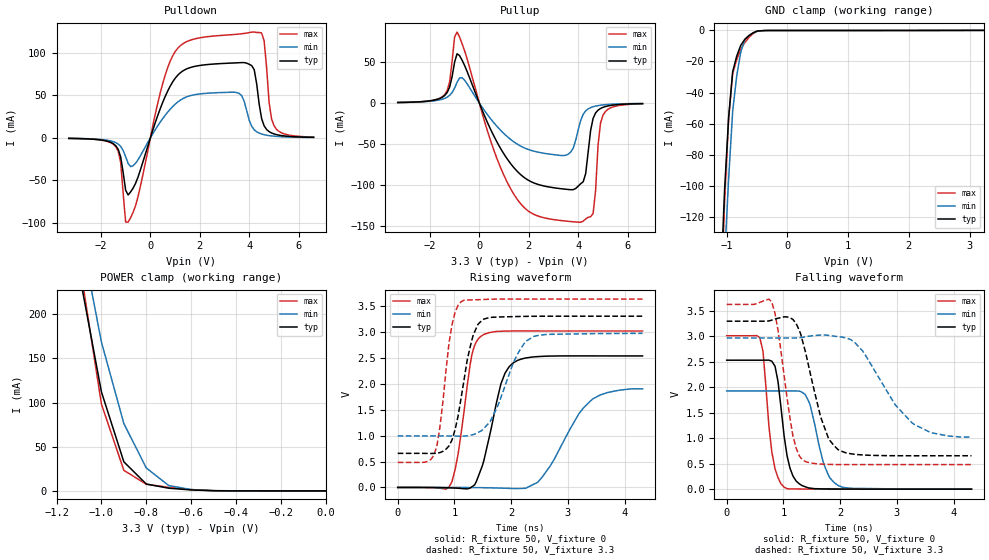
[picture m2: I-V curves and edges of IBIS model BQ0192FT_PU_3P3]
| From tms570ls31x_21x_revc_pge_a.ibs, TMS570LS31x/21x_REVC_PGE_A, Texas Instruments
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|   Model Cell BQ0192FT_PU_3P3
|BQ0192FT_PU_3P3
[Model]   BQ0192FT_PU_3P3
Model_type   I/O
Polarity   Non-Inverting
Enable   Active-Low
Vinl =  1.15
Vinh =  1.55
Cref =  15.0001pF
Rref =  101.0000M
Vref =  0V
Vmeas =  1.65
C_comp   1.2p   1.2p   1.2p
[Model Spec]
Vinl   1.15   1.02   1.28
Vinh   1.55   1.45   1.65
[Temperature Range]   25   155   -40
[Voltage Range]   3.3   2.97   3.63
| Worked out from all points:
|   slope of the pulldown table from 0 to 0.495 V, typ, clamps not added: 11.9 ohm
|   slope of the pullup table from 0 to 0.495 V, typ, clamps not added: 14.3 ohm
|   GND clamp passes 1 mA (typ) near -0.53 V on its own axis
|   POWER clamp passes 1 mA (typ) near -0.59 V on its own axis
|   rising waveform, R_fixture 50, V_fixture 0: 20-80 % time 315ps typ, 599ps min, 226ps max; typ from 0.001 V to 2.53 V
|   rising waveform, R_fixture 50, V_fixture 3.3: 20-80 % time 265ps typ, 431ps min, 200ps max; typ from 0.658 V to 3.3 V
|   falling waveform, R_fixture 50, V_fixture 0: 20-80 % time 182ps typ, 257ps min, 155ps max; typ from 2.53 V to 0.001 V
|   falling waveform, R_fixture 50, V_fixture 3.3: 20-80 % time 362ps typ, 701ps min, 238ps max; typ from 3.3 V to 0.658 V
[POWER_clamp]
|   voltage   I(typ)   I(min)   I(max)
-3.3V     4.054A     4.63A      4.887A
-1.1V     248.3mA    301mA      262.8mA
-1.067V   202.9mA    256.9mA    208mA
-1.033V   157.6mA    212.7mA    153.2mA
-1V       112.2mA    168.6mA    98.37mA
-900mV    32.94mA    76.25mA    23.31mA
-800mV    7.767mA    25.97mA    7.563mA
-700mV    3.087mA    6.069mA    4.066mA
-600mV    1.133mA    1.556mA    1.49mA
-500mV    225uA      392.2uA    256.9uA
0V        441.5pA    6.157nA    415.4pA
[Pulldown]
|   voltage   I(typ)   I(min)   I(max)
-3.3V     -593uA     -522.6uA   -580.3uA
-1.4V     -9.188mA   -5.565mA   -10.35mA
-1.2V     -22.55mA   -10.08mA   -29.13mA
-1V       -61.66mA   -22.23mA   -99.07mA
-900mV    -67.21mA   -30.1mA    -99.29mA
1V        70.16mA    39.61mA    101.5mA
3.5V      88.44mA    53.41mA    122.1mA
4.2V      80.27mA    9.542mA    124.6mA
4.6V      14.18mA    3.749mA    114.2mA
4.8V      7.418mA    2.695mA    42.04mA
5V        4.687mA    2.03mA     14.29mA
6.6V      680.4uA    493.7uA    947.4uA
[Pullup]
|   voltage   I(typ)   I(min)   I(max)
-3.3V     671.9uA    618.2uA    613.1uA
-1.4V     9.171mA    5.687mA    10.35mA
-900mV    59.98mA    25.21mA    86.35mA
600mV     -40.93mA   -24.46mA   -58.45mA
1.4V      -78.76mA   -47.34mA   -111.2mA
3.5V      -105mA     -63.56mA   -143.7mA
4.1V      -98.17mA   -21.1mA    -145.1mA
4.3V      -85.91mA   -9.61mA    -141.1mA
4.6V      -18.69mA   -4.516mA   -134.6mA
4.8V      -8.691mA   -3.128mA   -51.49mA
5V        -5.242mA   -2.297mA   -14.81mA
6.6V      -711.8uA   -541.3uA   -921.2uA
[GND_clamp]
|   voltage   I(typ)   I(min)   I(max)
-3.3V     -3.25A     -2.875A    -4.945A
-1.1V     -166.9mA   -205.1mA   -187mA
-1.033V   -102.8mA   -146.7mA   -110.1mA
-966.7mV  -55.98mA   -95.7mA    -57.04mA
-900mV    -26.57mA   -52.04mA   -27.83mA
-833.3mV  -16.54mA   -29.29mA   -18.85mA
-766.7mV  -9.604mA   -13.93mA   -12.19mA
-700mV    -5.772mA   -5.956mA   -7.84mA
-566.7mV  -1.652mA   -1.675mA   -2.192mA
-500mV    -488.4uA   -640.8uA   -598.2uA
-366.7mV  -105uA     -106.2uA   -156.1uA
3.233V    -4.592uA   15.81uA    -37.39uA
[Ramp]
| variable   typ   min   max
dV/dt_f   1.637582/0.373308n   1.222668/0.7344505n   1.95285/0.2451554n
dV/dt_r   1.538833/0.3171262n   1.171712/0.6246286n   1.829769/0.2270145n
R_load = 50
[Rising Waveform]
R_fixture = 50
V_fixture = 0
V_fixture_min = 0
V_fixture_max = 0
|   time   V(typ)   V(min)   V(max)
0s        737uV      653.5uV    806.3uV
956ps     -9.029mV   856uV      110mV
1.064ns   -14.23mV   785.1uV    641.2mV
1.304ns   10.47mV    -1.289mV   2.541V
1.468ns   350.4mV    -3.579mV   2.913V
1.82ns    1.998V     -11.86mV   3.01V
2.036ns   2.401V     -19.88mV   3.015V
2.468ns   2.522V     99.98mV    3.015V
3.44ns    2.535V     1.707V     3.015V
4.316ns   2.534V     1.901V     3.015V
[Rising Waveform]
R_fixture = 50
V_fixture = 3.3
V_fixture_min = 2.97
V_fixture_max = 3.63
|   time   V(typ)   V(min)   V(max)
0s        657.7mV    994.2mV    483.5mV
640ps     656.6mV    994.3mV    625.2mV
744ps     672mV      994.1mV    1.166V
956ps     913.3mV    991.3mV    3.132V
1.116ns   1.714V     988.9mV    3.576V
1.332ns   2.94V      1.018V     3.614V
1.52ns    3.245V     1.14V      3.622V
2.108ns   3.294V     2.563V     3.63V
2.396ns   3.298V     2.909V     3.63V
4.316ns   3.3V       2.969V     3.63V
[Falling Waveform]
R_fixture = 50
V_fixture = 0
V_fixture_min = 0
V_fixture_max = 0
|   time   V(typ)   V(min)   V(max)
0s        2.534V     1.931V     3.015V
584ps     2.534V     1.931V     2.976V
640ps     2.534V     1.931V     2.711V
852ps     2.416V     1.93V      400.5mV
1.012ns   1.05V      1.93V      40.9mV
1.224ns   160.9mV    1.931V     5.008mV
1.44ns    25.77mV    1.74V      2.791mV
1.712ns   6.125mV    493.6mV    1.361mV
1.964ns   3.581mV    73.03mV    1.112mV
4.316ns   831.4uV    1.471mV    808.7uV
[Falling Waveform]
R_fixture = 50
V_fixture = 3.3
V_fixture_min = 2.97
V_fixture_max = 3.63
|   time   V(typ)   V(min)   V(max)
0s        3.3V       2.97V      3.63V
796ps     3.322V     2.97V      3.674V
904ps     3.358V     2.97V      3.127V
1.168ns   3.334V     2.97V      1.044V
1.332ns   2.933V     2.983V     580.3mV
1.656ns   1.42V      3.027V     494.5mV
1.964ns   776.8mV    2.996V     484.1mV
2.396ns   672.8mV    2.717V     483.5mV
3.264ns   656.7mV    1.307V     483.6mV
4.316ns   657.5mV    1.024V     483.5mV
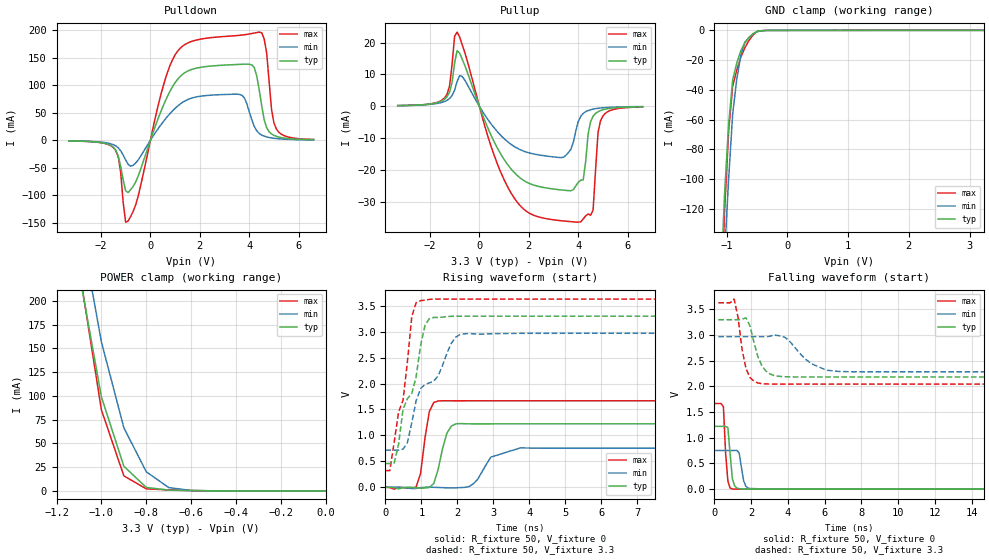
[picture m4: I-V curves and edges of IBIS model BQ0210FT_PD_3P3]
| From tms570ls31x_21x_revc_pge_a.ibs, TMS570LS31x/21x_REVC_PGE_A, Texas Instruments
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|   Model Cell BQ0210FT_PD_3P3
|BQ0210FT_PD_3P3
[Model]   BQ0210FT_PD_3P3
Model_type   I/O
Polarity   Non-Inverting
Enable   Active-Low
Vinl =  1.15
Vinh =  1.55
Cref =  15.0001pF
Rref =  101.0000M
Vref =  0V
Vmeas =  1.65
C_comp   1.2p   1.2p   1.2p
[Model Spec]
Vinl   1.15   1.02   1.28
Vinh   1.55   1.45   1.65
[Temperature Range]   25   155   -40
[Voltage Range]   3.3   2.97   3.63
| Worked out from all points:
|   slope of the pulldown table from 0 to 0.495 V, typ, clamps not added: 8.21 ohm
|   slope of the pullup table from 0 to 0.495 V, typ, clamps not added: 52.1 ohm
|   GND clamp passes 1 mA (typ) near -0.51 V on its own axis
|   POWER clamp passes 1 mA (typ) near -0.70 V on its own axis
|   rising waveform, R_fixture 50, V_fixture 0: 20-80 % time 262ps typ, 469ps min, 201ps max; typ from 0 V to 1.22 V
|   rising waveform, R_fixture 50, V_fixture 3.3: 20-80 % time 576ps typ, 968ps min, 420ps max; typ from 0.458 V to 3.3 V
|   falling waveform, R_fixture 50, V_fixture 0: 20-80 % time 181ps typ, 215ps min, 167ps max; typ from 1.22 V to 0 V
|   falling waveform, R_fixture 50, V_fixture 3.3: 20-80 % time 29.5ns typ, 30.7ns min, 18.4ns max; typ from 3.3 V to 0.465 V
[POWER_clamp]
|   voltage   I(typ)   I(min)   I(max)
-3.3V     4.048A     4.625A     4.878A
-1.1V     231mA      288.4mA    235.6mA
-1.067V   187mA      244.6mA    185.5mA
-1.033V   143mA      200.7mA    135.4mA
-1V       98.97mA    156.8mA    85.32mA
-900mV    25.98mA    66.53mA    15.87mA
-800mV    3.686mA    20.17mA    2.212mA
-700mV    860.3uA    3.509mA    1.065mA
-600mV    301.3uA    572.9uA    402.5uA
0V        19.75uA    8.573uA    38.26uA
[Pulldown]
|   voltage   I(typ)   I(min)   I(max)
-3.3V     -969uA     -848.2uA   -928.8uA
-1.4V     -17.91mA   -9.953mA   -18.22mA
-1V       -91.46mA   -35.59mA   -148.6mA
-900mV    -94.7mA    -43.39mA   -146.6mA
1.1V      110.9mA    62.3mA     162mA
3.7V      138.3mA    82.11mA    191.3mA
4.2V      132.3mA    25.59mA    195mA
4.4V      92.36mA    12.74mA    196.7mA
4.7V      23.23mA    6.307mA    159.7mA
4.9V      11.73mA    4.459mA    55.98mA
5.1V      7.323mA    3.326mA    20.29mA
6.6V      1.15mA     841.4uA    1.761mA
[Pullup]
|   voltage   I(typ)   I(min)   I(max)
-3.3V     170.4uA    161.9uA    202.8uA
-1.4V     2.221mA    1.492mA    2.652mA
-900mV    17.47mA    7.707mA    23.31mA
500mV     -9.587mA   -5.844mA   -13.22mA
1.4V      -20.78mA   -12.62mA   -28.76mA
3.4V      -26.42mA   -16.07mA   -36.11mA
4V        -23.95mA   -4.814mA   -36.5mA
4.2V      -23.22mA   -2.294mA   -35.5mA
4.6V      -3.167mA   -930.7uA   -32.71mA
4.8V      -1.739mA   -669.4uA   -8.284mA
5V        -1.12mA    -503.2uA   -3.036mA
6.6V      -167.4uA   -126.3uA   -220.9uA
[GND_clamp]
|   voltage   I(typ)   I(min)   I(max)
-3.3V     -3.252A    -2.876A    -4.947A
-1.1V     -174mA     -209.6mA   -199.1mA
-1.033V   -110.1mA   -151.3mA   -121.8mA
-966.7mV  -63.24mA   -100.2mA   -67.92mA
-900mV    -33.37mA   -56.38mA   -37.45mA
-833.3mV  -22.09mA   -33.02mA   -26.81mA
-766.7mV  -13.8mA    -16.89mA   -18.25mA
-700mV    -8.497mA   -8.009mA   -11.76mA
-566.7mV  -2.402mA   -2.404mA   -3.19mA
-500mV    -637.3uA   -910.4uA   -737.7uA
-300mV    -7.458uA   -14.47uA   -10.67uA
3.233V    19.75uA    9.688uA    38.26uA
[Ramp]
| variable   typ   min   max
dV/dt_f   1.740161/29.5039n   0.563632/0.4681303n   2.029677/18.39336n
dV/dt_r  0.7565115/0.2545289n  0.4743257/0.4324424n   1.024878/0.1944352n
R_load = 50
[Rising Waveform]
R_fixture = 50
V_fixture = 0
V_fixture_min = 0
V_fixture_max = 0
|   time   V(typ)   V(min)   V(max)
0s        -18.02uV   -11.09uV   -4.545uV
852ps     -9.366mV   -23.5mV    3.643mV
976ps     -18.71mV   -7.196mV   261.2mV
1.22ns    -3.971mV   997.2uV    1.46V
1.464ns   339.8mV    -4.063mV   1.664V
1.708ns   1.04V      -11.46mV   1.668V
2.076ns   1.228V     -7.487mV   1.667V
2.932ns   1.222V     580.4mV    1.668V
3.748ns   1.223V     758.5mV    1.668V
35.6ns    1.224V     752.9mV    1.668V
[Rising Waveform]
R_fixture = 50
V_fixture = 3.3
V_fixture_min = 2.97
V_fixture_max = 3.63
|   time   V(typ)   V(min)   V(max)
0s        457.5mV    717mV      321.9mV
120ps     457.5mV    717mV      321.3mV
244ps     469.6mV    717mV      876.4mV
488ps     1.503V     734.1mV    1.679V
732ps     1.811V     1.242V     3.294V
976ps     2.729V     1.903V     3.6V
1.22ns    3.25V      2.013V     3.623V
1.956ns   3.298V     2.894V     3.629V
2.32ns    3.299V     2.964V     3.629V
35.6ns    3.3V       2.97V      3.629V
[Falling Waveform]
R_fixture = 50
V_fixture = 0
V_fixture_min = 0
V_fixture_max = 0
|   time   V(typ)   V(min)   V(max)
0s        1.224V     752.9mV    1.668V
488ps     1.223V     752.9mV    1.606V
608ps     1.222V     752.9mV    694.9mV
732ps     1.2V       752.9mV    155.6mV
976ps     201.6mV    752.2mV    3.622mV
1.1ns     62.87mV    752.6mV    1.41mV
1.344ns   9.411mV    706.1mV    910.9uV
1.588ns   2.341mV    165.7mV    1.029mV
1.956ns   805.6uV    12.92mV    675.6uV
35.6ns    157uV      3.513uV    2.071uV
[Falling Waveform]
R_fixture = 50
V_fixture = 3.3
V_fixture_min = 2.97
V_fixture_max = 3.63
|   time   V(typ)   V(min)   V(max)
212ps     3.3V       2.97V      3.629V
1.072ns   3.299V     2.97V      3.702V
1.716ns   3.335V     2.97V      2.349V
2.364ns   2.582V     2.97V      2.068V
18.34ns   2.185V     2.285V     2.05V
20.97ns   2.185V     2.285V     477mV
29.3ns    2.186V     2.285V     345mV
34.98ns   551.4mV    2.285V     344.8mV
36.08ns   525.4mV    755.6mV    344.8mV
36.96ns   465.4mV    755.6mV    344.8mV
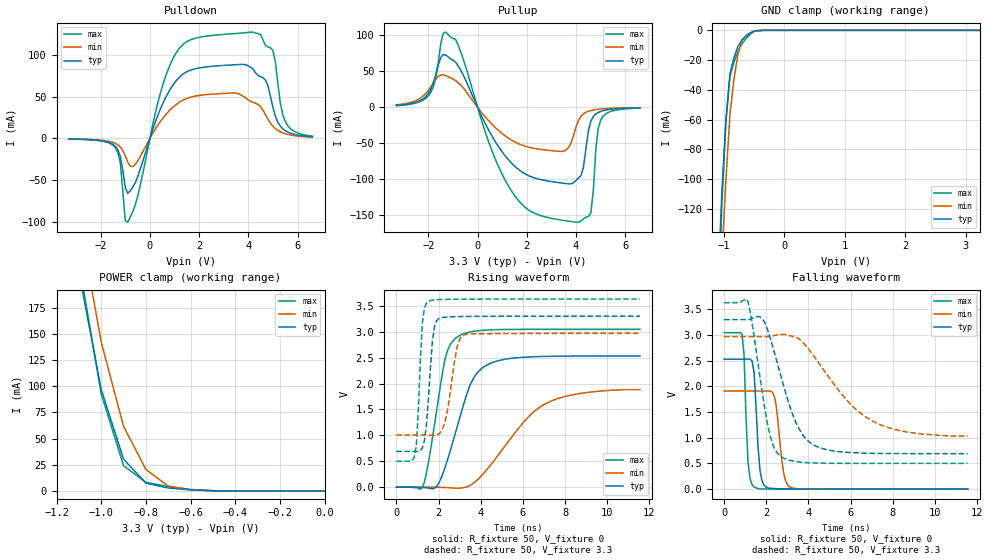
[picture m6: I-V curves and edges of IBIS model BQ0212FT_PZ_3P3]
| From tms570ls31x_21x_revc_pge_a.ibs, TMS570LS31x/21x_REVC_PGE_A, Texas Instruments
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|   Model Cell BQ0212FT_PZ_3P3
|BQ0212FT_PZ_3P3
[Model]   BQ0212FT_PZ_3P3
Model_type   I/O
Polarity   Non-Inverting
Enable   Active-Low
Vinl =  1.15
Vinh =  1.55
Cref =  15.0001pF
Rref =  101.0000M
Vref =  0V
Vmeas =  1.65
C_comp   1.2p   1.2p   1.2p
[Model Spec]
Vinl   1.15   1.02   1.28
Vinh   1.55   1.45   1.65
[Temperature Range]   25   155   -40
[Voltage Range]   3.3   2.97   3.63
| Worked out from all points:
|   slope of the pulldown table from 0 to 0.495 V, typ, clamps not added: 12.4 ohm
|   slope of the pullup table from 0 to 0.495 V, typ, clamps not added: 14.3 ohm
|   GND clamp passes 1 mA (typ) near -0.53 V on its own axis
|   POWER clamp passes 1 mA (typ) near -0.60 V on its own axis
|   rising waveform, R_fixture 50, V_fixture 0: 20-80 % time 1.15ns typ, 2.3ns min, 717ps max; typ from 0 V to 2.53 V
|   rising waveform, R_fixture 50, V_fixture 3.3: 20-80 % time 274ps typ, 440ps min, 218ps max; typ from 0.691 V to 3.3 V
|   falling waveform, R_fixture 50, V_fixture 0: 20-80 % time 219ps typ, 306ps min, 166ps max; typ from 2.53 V to 0 V
|   falling waveform, R_fixture 50, V_fixture 3.3: 20-80 % time 1.2ns typ, 2.39ns min, 724ps max; typ from 3.3 V to 0.691 V
[POWER_clamp]
|   voltage   I(typ)   I(min)   I(max)
-3.3V     3.99A      4.579A     4.788A
-1.1V     209.6mA    262.2mA    219.1mA
-1.067V   172.1mA    222.3mA    177mA
-1.033V   134.5mA    182.3mA    134.9mA
-1V       96.96mA    142.4mA    92.74mA
-900mV    30.4mA     61.8mA     24.2mA
-800mV    7.444mA    20.57mA    8.211mA
-700mV    2.829mA    4.587mA    4.192mA
-600mV    931uA      1.084mA    1.431mA
-500mV    136.9uA    230.8uA    190.6uA
0V        457.7pA    5.751nA    460.2pA
[Pulldown]
|   voltage   I(typ)   I(min)   I(max)
-3.3V     -649.5uA   -582.6uA   -652.5uA
-1.4V     -9.531mA   -5.889mA   -11.14mA
-1.2V     -22.05mA   -10.26mA   -29.81mA
-1V       -58.85mA   -20.91mA   -98.56mA
-900mV    -65.57mA   -28.22mA   -100.1mA
400mV     33.51mA    19.22mA    51.63mA
1.1V      70.16mA    41.36mA    104mA
4.1V      85.11mA    44.32mA    127.2mA
4.7V      69.58mA    28.18mA    111.1mA
5V        36.79mA    14.44mA    104.9mA
5.5V      9.351mA    5.597mA    20.3mA
6.6V      2.027mA    1.639mA    2.825mA
[Pullup]
|   voltage   I(typ)   I(min)   I(max)
-3.3V     2.63mA     3.499mA    2.212mA
-1.9V     24.96mA    28.62mA    20.66mA
-1.3V     72.58mA    44.01mA    104.4mA
-800mV    58.09mA    34.42mA    87.14mA
500mV     -34.83mA   -20.49mA   -52.76mA
1.5V      -81.5mA    -47.85mA   -122.3mA
3.5V      -105.5mA   -60.79mA   -157.1mA
4.1V      -98.13mA   -18.32mA   -159.5mA
4.6V      -19.34mA   -4.48mA    -147.3mA
4.8V      -9.331mA   -3.151mA   -59.41mA
5V        -5.707mA   -2.337mA   -17.88mA
6.6V      -794.7uA   -560.5uA   -1.138mA
[GND_clamp]
|   voltage   I(typ)   I(min)   I(max)
-3.3V     -3.259A    -2.879A    -4.965A
-1.1V     -172mA     -209.5mA   -194.3mA
-1.033V   -107.5mA   -151.2mA   -115.6mA
-966.7mV  -59.81mA   -100mA     -61.11mA
-900mV    -29.01mA   -56.02mA   -30.69mA
-833.3mV  -18.19mA   -32.15mA   -21.24mA
-766.7mV  -10.62mA   -15.71mA   -14.04mA
-700mV    -6.305mA   -6.695mA   -9.073mA
-566.7mV  -1.758mA   -1.718mA   -2.644mA
-500mV    -452.5uA   -560.7uA   -673.7uA
-366.7mV  -18.36uA   -44.65uA   -24.3uA
3.233V    436.7pA    2.447uA    352.2pA
[Ramp]
| variable   typ   min   max
dV/dt_f   1.605245/1.221302n   1.205209/2.499758n   1.923697/0.7350988n
dV/dt_r   1.538075/1.159576n   1.158222/2.384531n   1.850861/0.7236556n
R_load = 50
[Rising Waveform]
R_fixture = 50
V_fixture = 0
V_fixture_min = 0
V_fixture_max = 0
|   time   V(typ)   V(min)   V(max)
0s        -3.701uV   -1.554uV   -4.297uV
1.232ns   -5.493mV   -3.367uV   -11.61mV
1.424ns   -10.63mV   65.99uV    268.5mV
1.8ns     -21.67mV   -148.6uV   1.186V
2.276ns   343.7mV    -5.924mV   2.408V
2.9ns     1.19V      -20.4mV    2.9V
3.684ns   2.122V     86.17mV    3.009V
4.472ns   2.392V     431mV      3.036V
7.084ns   2.524V     1.614V     3.046V
11.56ns   2.531V     1.881V     3.046V
[Rising Waveform]
R_fixture = 50
V_fixture = 3.3
V_fixture_min = 2.97
V_fixture_max = 3.63
|   time   V(typ)   V(min)   V(max)
0s        690.7mV    1.006V     501.4mV
852ps     689.5mV    1.006V     587.1mV
948ps     686.4mV    1.006V     819.4mV
1.232ns   763.8mV    1.006V     3.171V
1.516ns   1.676V     1.004V     3.585V
1.708ns   2.812V     998.7mV    3.608V
1.896ns   3.201V     1.003V     3.619V
2.34ns    3.281V     1.317V     3.624V
3.152ns   3.294V     2.93V      3.627V
11.56ns   3.3V       2.97V      3.63V
[Falling Waveform]
R_fixture = 50
V_fixture = 0
V_fixture_min = 0
V_fixture_max = 0
|   time   V(typ)   V(min)   V(max)
0s        2.531V     1.91V      3.046V
852ps     2.531V     1.91V      3.017V
1.136ns   2.532V     1.91V      540.4mV
1.424ns   2.272V     1.91V      42.01mV
1.708ns   353.5mV    1.909V     6.563mV
1.992ns   40.88mV    1.91V      3.128mV
2.4ns     12.63mV    1.783V     1.786mV
2.84ns    4.07mV     295.3mV    991.3uV
3.152ns   2.716mV    35.85mV    631.2uV
11.56ns   8.159uV    139.2uV    6.695uV
[Falling Waveform]
R_fixture = 50
V_fixture = 3.3
V_fixture_min = 2.97
V_fixture_max = 3.63
|   time   V(typ)   V(min)   V(max)
0s        3.3V       2.97V      3.63V
1.136ns   3.299V     2.97V      3.65V
1.708ns   3.351V     2.97V      2.173V
2.088ns   3.079V     2.97V      1.218V
2.34ns    2.731V     2.987V     839.7mV
2.716ns   2.173V     3.01V      632.7mV
3.528ns   1.196V     2.931V     530.9mV
4.472ns   818mV      2.468V     507.9mV
7.084ns   697.8mV    1.317V     501.5mV
11.56ns   690.6mV    1.036V     501.4mV
